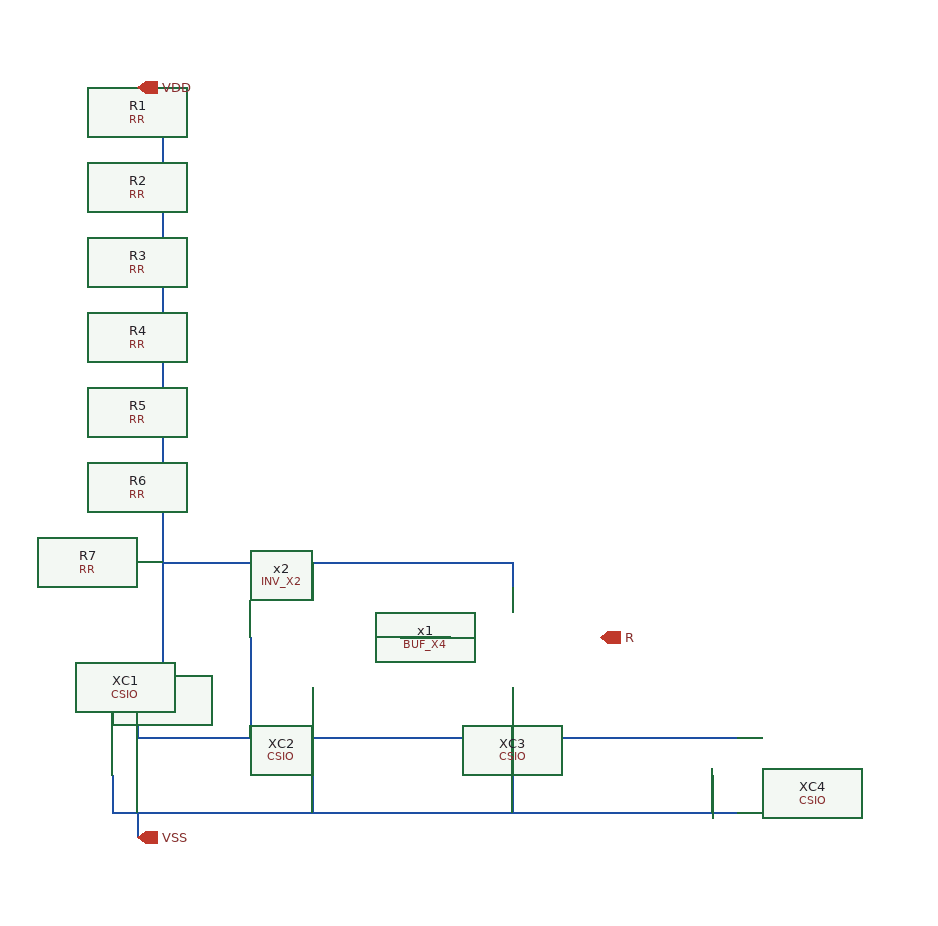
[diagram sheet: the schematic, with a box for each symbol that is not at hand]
v {xschem version=3.4.8RC file_version=1.3}
G {}
K {}
V {}
S {}
F {}
E {}
N 40 -20 40 -0 {lab=VDD}
N 60 0 60 450 {lab=VDD}
N 40 -0 60 0 {lab=VDD}
N 40 480 40 500 {lab=#net1}
N 20 530 20 560 {lab=VSS}
N 20 560 520 560 {lab=VSS}
N 40 560 40 580 {lab=VSS}
N 40 500 520 500 {lab=#net1}
N 180 530 180 560 {lab=VSS}
N 340 530 340 560 {lab=VSS}
N 500 530 500 560 {lab=VSS}
N 180 360 180 380 {lab=VDD}
N 340 360 340 380 {lab=VDD}
N 180 460 180 530 {lab=VSS}
N 340 460 340 530 {lab=VSS}
N 130 420 130 500 {lab=#net1}
N 250 420 290 420 {lab=#net2}
N 60 360 340 360 {lab=VDD}
C {TR-1umLIB/RR.sym} 40 0 0 0 {name=R1
w=2.8e-06
R=1
l=60e-06
model=F_RR
spiceprefix=X
tc1=0
tc2=0
m=1}
C {TR-1umLIB/RR.sym} 40 60 0 0 {name=R2
w=2.8e-06
R=1
l=60e-06
model=F_RR
spiceprefix=X
tc1=0
tc2=0
m=1}
C {TR-1umLIB/RR.sym} 40 120 0 0 {name=R3
w=2.8e-06
R=1
l=60e-06
model=F_RR
spiceprefix=X
tc1=0
tc2=0
m=1}
C {TR-1umLIB/RR.sym} 40 180 0 0 {name=R4
w=2.8e-06
R=1
l=60e-06
model=F_RR
spiceprefix=X
tc1=0
tc2=0
m=1}
C {TR-1umLIB/RR.sym} 40 240 0 0 {name=R5
w=2.8e-06
R=1
l=60e-06
model=F_RR
spiceprefix=X
tc1=0
tc2=0
m=1}
C {TR-1umLIB/RR.sym} 40 300 0 0 {name=R6
w=2.8e-06
R=1
l=60e-06
model=F_RR
spiceprefix=X
tc1=0
tc2=0
m=1}
C {TR-1umLIB/RR.sym} 40 360 0 0 {name=R7
w=2.8e-06
R=1
l=60e-06
model=F_RR
spiceprefix=X
tc1=0
tc2=0
m=1}
C {TR-1umLIB/RR.sym} 40 420 0 0 {name=R8
w=2.8e-06
R=1
l=60e-06
model=F_RR
spiceprefix=X
tc1=0
tc2=0
m=1}
C {devices/iopin.sym} 40 -20 0 1 {name=p1 lab=VDD}
C {TR-1umLIB/CSIO.sym} 40 500 0 0 {name=XC1
model=F_CSIO
spiceprefix=X
x=110.0u
y=110.0u
c="expr_eng( 0.6e-3 * @x * @y )"
a="expr_eng( @x * @y )"
p="expr_eng( 2 * ( @x + @y ) )"
m=1}
C {TR-1umLIB/CSIO.sym} 200 500 0 0 {name=XC2
model=F_CSIO
spiceprefix=X
x=110.0u
y=110.0u
c="expr_eng( 0.6e-3 * @x * @y )"
a="expr_eng( @x * @y )"
p="expr_eng( 2 * ( @x + @y ) )"
m=1}
C {TR-1umLIB/CSIO.sym} 360 500 0 0 {name=XC3
model=F_CSIO
spiceprefix=X
x=110.0u
y=110.0u
c="expr_eng( 0.6e-3 * @x * @y )"
a="expr_eng( @x * @y )"
p="expr_eng( 2 * ( @x + @y ) )"
m=1}
C {TR-1umLIB/CSIO.sym} 520 500 0 0 {name=XC4
model=F_CSIO
spiceprefix=X
x=110.0u
y=110.0u
c="expr_eng( 0.6e-3 * @x * @y )"
a="expr_eng( @x * @y )"
p="expr_eng( 2 * ( @x + @y ) )"
m=1}
C {devices/iopin.sym} 40 580 0 1 {name=p2 lab=VSS}
C {TR-1um_5_stdcell/INV_X2.sym} 150 420 0 0 {name=x2}
C {devices/opin.sym} 410 420 0 0 {name=p3 lab=R}
C {TR-1um_5_stdcell/BUF_X4.sym} 310 420 0 0 {name=x1}
